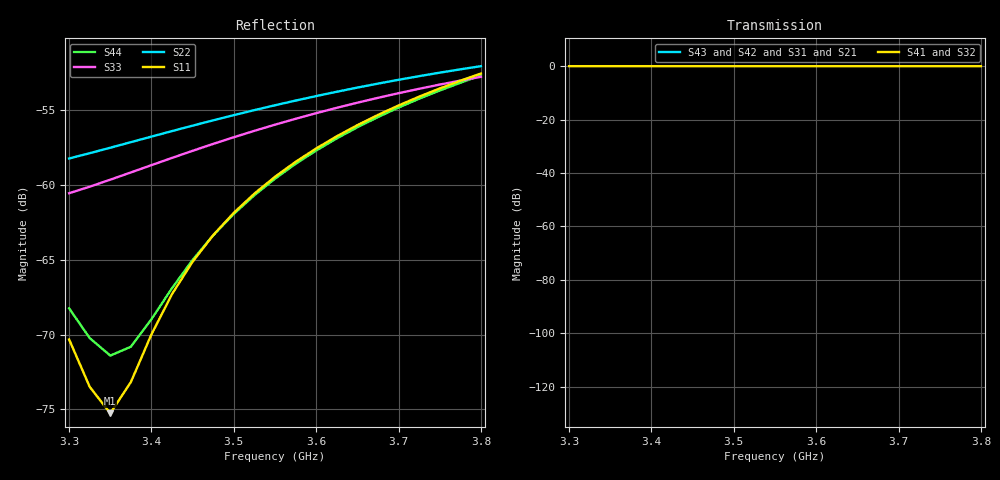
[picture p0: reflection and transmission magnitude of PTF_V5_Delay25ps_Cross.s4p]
! Touchstone file exported from HFSS 2025.2.4
!  File:  C:/Users/devel/OneDrive/Documents/Velocity-Connect/hfss/Velocity_Connect_PTF_V5_FourPort_Delay25ps.aedt
!  Generated:  02:44:13 PM Aug 25, 2026
!  Design:  VC_PTF_V5_FourPortDelay25ps
!  Project:  Velocity_Connect_PTF_V5_FourPort_Delay25ps
# GHz S RI R 50.000000
! Terminal data exported
! Port[1] = Port1_DonorMinus
! Port[2] = Port2_DonorPlus
! Port[3] = Port3_ServiceMinus
! Port[4] = Port4_ServicePlus
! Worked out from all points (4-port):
!   21 points, 3.3 GHz to 3.8 GHz, reference 50 ohm
!   strongest paths, dB at 3.3 GHz, 3.425 GHz, 3.55 GHz, 3.675 GHz, 3.8 GHz:
!     S41: 0.0, 0.0, 0.0, 0.0, 0.0
!     S32: 0.0, 0.0, 0.0, 0.0, 0.0
!     S43: -, -, -, -, -
!     S42: -, -, -, -, -
!     S31: -, -, -, -, -
!     S21: -, -, -, -, -
!   lowest |S11| = -75.3 dB at 3.35 GHz (marker M1), VSWR 1.00, Z = 50 + j0.00304 ohm
!   |S11| at or under -10 dB: start of sweep to end of sweep
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3.3  0.000102 0.000287  0 0  0 0  -0.9895 -0.1277
     0 0  0.00078 -0.000945  -0.9228 0.3784  0 0
     0 0  -0.9228 0.3784  -0.000902 -0.000256  0 0
     -0.9895 -0.1277  0 0  0 0  -0.000312 0.000229
3.35  0.00017 3.04e-05  0 0  0 0  -0.9943 -0.0824
      0 0  0.000654 -0.00116  -0.9012 0.4272  0 0
      0 0  -0.9012 0.4272  -0.000964 -0.000394  0 0
      -0.9943 -0.0824  0 0  0 0  -0.000269 -1.02e-05
3.375  0.000195 -0.000101  0 0  0 0  -0.9959 -0.0597
       0 0  0.000583 -0.00126  -0.8895 0.4511  0 0
       0 0  -0.8895 0.4511  -0.001 -0.00046  0 0
       -0.9959 -0.0597  0 0  0 0  -0.000256 -0.000132
3.45  0.000236 -0.000502  0 0  0 0  -0.9976 0.00854
      0 0  0.000339 -0.00154  -0.8504 0.5209  0 0
      0 0  -0.8504 0.5209  -0.00113 -0.000642  0 0
      -0.9976 0.00854  0 0  0 0  -0.000254 -0.000501
3.525  0.000222 -0.000909  0 0  0 0  -0.9947 0.0768
       0 0  5.69e-05 -0.00178  -0.8059 0.5874  0 0
       0 0  -0.8059 0.5874  -0.00129 -0.000797  0 0
       -0.9947 0.0768  0 0  0 0  -0.000305 -0.000872
3.65  7.88e-05 -0.00158  0 0  0 0  -0.9794 0.1895
      0 0  -0.00048 -0.00206  -0.7204 0.6895  0 0
      0 0  -0.7204 0.6895  -0.0016 -0.000986  0 0
      -0.9794 0.1895  0 0  0 0  -0.00051 -0.00147
3.8  -0.000287 -0.00234  0 0  0 0  -0.9443 0.3214
     0 0  -0.00118 -0.00219  -0.601 0.7957  0 0
     0 0  -0.601 0.7957  -0.00202 -0.00108  0 0
     -0.9443 0.3214  0 0  0 0  -0.000943 -0.00212
